VERSION 5.8 ;
BUSBITCHARS "[]" ;
DIVIDERCHAR "/" ;

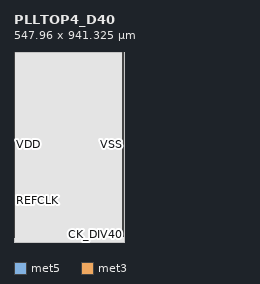
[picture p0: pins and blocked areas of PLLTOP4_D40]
MACRO PLLTOP4_D40
  CLASS BLOCK ;
  FOREIGN PLLTOP4_D40 0 0 ;
  ORIGIN 0 0 ;
  SIZE 547.960 BY 941.325 ;
  SYMMETRY X Y R90 ;
  PIN VDD
    DIRECTION INOUT ;
    USE POWER ;
    PORT
      LAYER met5 ;
        RECT 0.000 22.325 4.000 941.325 ;
    END
  END VDD
  PIN VSS
    DIRECTION INOUT ;
    USE GROUND ;
    PORT
      LAYER met5 ;
        RECT 537.660 26.325 541.660 937.325 ;
    END
  END VSS
  PIN REFCLK
    DIRECTION INPUT ;
    USE SIGNAL ;
    PORT
      LAYER met3 ;
        RECT 53.770 207.400 54.430 208.060 ;
    END
  END REFCLK
  PIN PLL_CLK
    DIRECTION OUTPUT ;
    USE SIGNAL ;
    PORT
      LAYER met3 ;
        RECT 238.360 218.460 240.360 218.780 ;
    END
  END PLL_CLK
  PIN CK_DIV40
    DIRECTION OUTPUT ;
    USE SIGNAL ;
    PORT
      LAYER met3 ;
        RECT 546.960 11.885 547.960 12.205 ;
    END
  END CK_DIV40
  OBS
    LAYER li1 ;
      RECT 0.000 0.000 547.960 941.325 ;
    LAYER met1 ;
      RECT 0.000 0.000 547.960 941.325 ;
    LAYER met2 ;
      RECT 0.000 0.000 547.960 941.325 ;
  END
END PLLTOP4_D40

END LIBRARY
